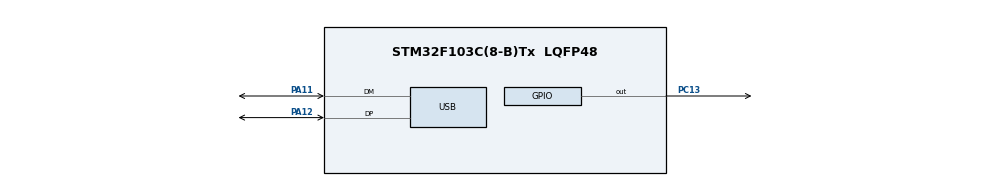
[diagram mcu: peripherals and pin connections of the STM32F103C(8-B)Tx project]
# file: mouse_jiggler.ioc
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Mcu.Family=STM32F1
Mcu.Name=STM32F103C(8-B)Tx
Mcu.Package=LQFP48
NVIC.PriorityGroup=NVIC_PRIORITYGROUP_4
NVIC.USB_LP_CAN1_RX0_IRQn=true\:0\:0\:false\:false\:true\:false\:true\:true
PA11.Mode=Device
PA11.Signal=USB_DM
PA12.Mode=Device
PA12.Signal=USB_DP
PA13.Mode=Serial_Wire
PA13.Signal=SYS_JTMS-SWDIO
PA14.Mode=Serial_Wire
PA14.Signal=SYS_JTCK-SWCLK
PC13-TAMPER-RTC.Signal=GPIO_Output
PD0-OSC_IN.Mode=HSE-External-Oscillator
PD0-OSC_IN.Signal=RCC_OSC_IN
PD1-OSC_OUT.Mode=HSE-External-Oscillator
PD1-OSC_OUT.Signal=RCC_OSC_OUT
ProjectManager.HeapSize=0x1000
ProjectManager.StackSize=0x1000
ProjectManager.TargetToolchain=STM32CubeIDE
RCC.AHBFreq_Value=72000000
RCC.APB1CLKDivider=RCC_HCLK_DIV2
RCC.APB1Freq_Value=36000000
RCC.APB1TimFreq_Value=72000000
RCC.APB2Freq_Value=72000000
RCC.APB2TimFreq_Value=72000000
RCC.HCLKFreq_Value=72000000
RCC.PLLMUL=RCC_PLL_MUL9
RCC.SYSCLKFreq_VALUE=72000000
RCC.SYSCLKSource=RCC_SYSCLKSOURCE_PLLCLK
RCC.USBFreq_Value=48000000
RCC.USBPrescaler=RCC_USBCLKSOURCE_PLL_DIV1_5
USB_DEVICE.CLASS_NAME_FS=HID
USB_DEVICE.VirtualMode=Hid
USB_DEVICE.VirtualModeFS=Hid_FS
VP_USB_DEVICE_VS_USB_DEVICE_HID_FS.Mode=HID_FS
board=custom

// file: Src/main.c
/* USER CODE BEGIN Header */
/**
  ******************************************************************************
  * @file           : main.c
  * @brief          : Main program body
  ******************************************************************************
  * @attention
  *
  * Copyright (c) 2026 STMicroelectronics.
  * All rights reserved.
  *
  * This software is licensed under terms that can be found in the LICENSE file
  * in the root directory of this software component.
  * If no LICENSE file comes with this software, it is provided AS-IS.
  *
  ******************************************************************************
  */
/* USER CODE END Header */
#include "main.h"
#include "usb_device.h"

/* USER CODE BEGIN Includes */
#include <stdlib.h>
#include <math.h>
#include "usbd_def.h"
#include "usbd_hid.h"
/* USER CODE END Includes */

/* USER CODE BEGIN PD */

#ifndef M_PI
#define M_PI 3.14159265358979323846
#endif

#define STARTUP_DELAY_MS   3000
#define LED_BLINK_WAIT_MS  1000   // full period while waiting (USB OK)
#define LED_BLINK_WORK_MS  500    // full period while moving
#define LED_BLINK_NO_HOST_MS 150  // continuous fast blink: no host setup packets
#define LED_DBG_CYCLE_MS     2500 // pause between burst groups
#define LED_DBG_SLOT_MS      400  // one blink slot within a burst
#define LED_DBG_ON_MS        200  // on-time within each slot

/* Jiggler movement tuning */
#define JIGGLE_WAIT_MIN_MS      3000
#define JIGGLE_WAIT_RANGE_MS    5000   // 3-8 s between moves
#define JIGGLE_STEP_MIN_MS      16
#define JIGGLE_STEP_RANGE_MS      8    // 16-24 ms between HID updates
#define JIGGLE_MOVE_MIN_MS       900
#define JIGGLE_MOVE_RANGE_MS     600   // each move lasts 0.9-1.5 s
#define JIGGLE_MAX_DELTA           2   // pixels per report

/*
 * USB on STM32F103 needs 72 MHz PLL -> 48 MHz USB clock.
 *   USE_HSI_CLOCK 0  - HSE crystal (recommended; use BOARD_HSE_MHZ)
 *   USE_HSI_CLOCK 1  - HSI only (64 MHz max; USB clock out of spec, test only)
 *   BOARD_HSE_MHZ  8  - crystal marked 8.000 (PLL x9)
 *   BOARD_HSE_MHZ 12  - crystal marked 12.000 (PLL x6)
 */
#ifndef USE_HSI_CLOCK
#define USE_HSI_CLOCK 0
#endif
#ifndef BOARD_HSE_MHZ
#define BOARD_HSE_MHZ 8
#endif

/* USER CODE END PD */

/* USER CODE BEGIN PV */
/* ---- App state machine ---- */
typedef enum { APP_STARTUP, APP_WAITING, APP_MOVING } AppState;
static AppState app_state = APP_STARTUP;

static uint32_t startup_tick = 0;
static uint32_t led_last_toggle = 0;
static uint8_t  led_state = 0;
static uint8_t  startup_started = 0;

/* ---- Jiggler state ---- */
typedef enum { JIGGLE_WAITING, JIGGLE_MOVING } JiggleState;
static JiggleState jiggle_state = JIGGLE_WAITING;

static uint32_t next_action_tick = 0;
static uint32_t last_step_tick = 0;

static float ellipse_a;
static float ellipse_b;
static float rotation;
static float start_angle;
static float sweep_angle;
static float sent_x, sent_y;
static uint32_t step_interval_ms;
static uint32_t move_start_tick;
static uint32_t move_duration_ms;

static uint8_t hid_report[4] = {0};
extern USBD_HandleTypeDef hUsbDeviceFS;

/* USER CODE END PV */

void SystemClock_Config(void);
static void MX_GPIO_Init(void);

/* USER CODE BEGIN 0 */

/* ---------- LED helpers ---------- */
/* Blue Pill onboard LED is active-LOW: pin LOW = LED on.
   If your clone is inverted, swap SET/RESET in both functions below. */
static void led_toggle(void)
{
    led_state = !led_state;
    HAL_GPIO_WritePin(GPIOC, GPIO_PIN_13, led_state ? GPIO_PIN_RESET : GPIO_PIN_SET);
}

static void led_off(void)
{
    HAL_GPIO_WritePin(GPIOC, GPIO_PIN_13, GPIO_PIN_SET);
    led_state = 0;
}

/* Not configured: fast blink = no setup packets; N blinks/cycle = dev_state (1 or 2). */
static void led_usb_not_configured(uint32_t now)
{
    static uint32_t cycle_start = 0U;
    static uint8_t cycle_started = 0U;

    if (USB_GetSetupCount() == 0U)
    {
        cycle_started = 0U;
        if (now - led_last_toggle >= LED_BLINK_NO_HOST_MS / 2U)
        {
            led_toggle();
            led_last_toggle = now;
        }
        return;
    }

    if (!cycle_started)
    {
        cycle_start = now;
        cycle_started = 1U;
        led_off();
    }

    uint8_t blinks = USB_GetDevState();
    if (blinks < 1U)
    {
        blinks = 1U;
    }
    if (blinks > 4U)
    {
        blinks = 4U;
    }

    uint32_t elapsed = now - cycle_start;
    if (elapsed >= LED_DBG_CYCLE_MS)
    {
        cycle_start = now;
        elapsed = 0U;
        led_off();
    }

    uint32_t slot = elapsed / LED_DBG_SLOT_MS;
    uint32_t in_slot = elapsed % LED_DBG_SLOT_MS;

    if (slot < blinks)
    {
        uint8_t on = (in_slot < LED_DBG_ON_MS) ? 1U : 0U;
        if (on != led_state)
        {
            if (on)
            {
                HAL_GPIO_WritePin(GPIOC, GPIO_PIN_13, GPIO_PIN_RESET);
            }
            else
            {
                HAL_GPIO_WritePin(GPIOC, GPIO_PIN_13, GPIO_PIN_SET);
            }
            led_state = on;
        }
    }
    else
    {
        led_off();
    }
}

/* ---------- HID send ---------- */
static uint8_t hid_endpoint_ready(void)
{
    uint8_t state = hUsbDeviceFS.dev_state;

    if (state != USBD_STATE_CONFIGURED && state != USBD_STATE_SUSPENDED)
        return 0;
    if (hUsbDeviceFS.pClassData == NULL)
        return 0;

    USBD_HID_HandleTypeDef *hhid = (USBD_HID_HandleTypeDef *)hUsbDeviceFS.pClassData;
    return (hhid->state == HID_IDLE);
}

/* Returns 1 if the report was accepted by the USB stack. */
static uint8_t send_hid_move(int8_t dx, int8_t dy)
{
    USBD_HID_HandleTypeDef *hhid;

    if (!hid_endpoint_ready())
        return 0;

    hid_report[0] = 0;
    hid_report[1] = (uint8_t)dx;
    hid_report[2] = (uint8_t)dy;
    hid_report[3] = 0;
    USBD_HID_SendReport(&hUsbDeviceFS, hid_report, 4);

    hhid = (USBD_HID_HandleTypeDef *)hUsbDeviceFS.pClassData;
    return (hhid != NULL && hhid->state == HID_BUSY);
}

/* ---------- random helper ---------- */
static float randf(float min, float max)
{
    return min + ((float)rand() / (float)RAND_MAX) * (max - min);
}

static int8_t clamp_delta(int v)
{
    if (v > JIGGLE_MAX_DELTA)
        return (int8_t)JIGGLE_MAX_DELTA;
    if (v < -JIGGLE_MAX_DELTA)
        return (int8_t)(-JIGGLE_MAX_DELTA);
    return (int8_t)v;
}

/* ---------- ellipse math ---------- */
static void ellipse_point(float t, float *x, float *y)
{
    float ex = ellipse_a * cosf(t);
    float ey = ellipse_b * sinf(t);
    *x = ex * cosf(rotation) - ey * sinf(rotation);
    *y = ex * sinf(rotation) + ey * cosf(rotation);
}

/* ---------- start a new curved move ---------- */
static void start_new_move(void)
{
    uint32_t now = HAL_GetTick();

    ellipse_a   = randf(12.0f, 28.0f);
    ellipse_b   = randf(8.0f, 20.0f);
    rotation    = randf(0.0f, 2.0f * M_PI);
    start_angle = randf(0.0f, 2.0f * M_PI);
    sweep_angle = randf(M_PI * 0.6f, M_PI * 1.6f);
    if (rand() % 2) sweep_angle = -sweep_angle;

    sent_x = 0.0f;
    sent_y = 0.0f;
    move_start_tick = now;
    move_duration_ms = JIGGLE_MOVE_MIN_MS + (rand() % (JIGGLE_MOVE_RANGE_MS + 1));
    step_interval_ms = JIGGLE_STEP_MIN_MS + (rand() % (JIGGLE_STEP_RANGE_MS + 1));

    jiggle_state = JIGGLE_MOVING;
    last_step_tick = now;
}

/* ---------- advance one step of the current move ---------- */
static void jiggler_step(void)
{
    uint32_t now = HAL_GetTick();
    float move_t, eased, angle, x, y, dx, dy;
    int8_t idx, idy;
    uint32_t elapsed;

    if (now - last_step_tick < step_interval_ms)
        return;

    elapsed = now - move_start_tick;
    move_t = (float)elapsed / (float)move_duration_ms;
    if (move_t > 1.0f)
        move_t = 1.0f;

    eased = 0.5f - 0.5f * cosf(move_t * (float)M_PI);
    angle = start_angle + sweep_angle * eased;
    ellipse_point(angle, &x, &y);

    dx = x - sent_x;
    dy = y - sent_y;

    /* Move complete: duration elapsed and cursor caught up to the path. */
    if (move_t >= 1.0f && (dx * dx + dy * dy) < 4.0f)
    {
        jiggle_state = JIGGLE_WAITING;
        next_action_tick = now + (JIGGLE_WAIT_MIN_MS + (rand() % (JIGGLE_WAIT_RANGE_MS + 1)));
        last_step_tick = now;
        return;
    }

    if (fabsf(dx) < 0.01f && fabsf(dy) < 0.01f)
    {
        last_step_tick = now;
        return;
    }

    idx = clamp_delta((int)roundf(dx));
    idy = clamp_delta((int)roundf(dy));

    if (idx == 0 && idy == 0)
    {
        if (fabsf(dx) >= fabsf(dy))
            idx = (dx > 0.0f) ? 1 : -1;
        else
            idy = (dy > 0.0f) ? 1 : -1;
    }

    if (!send_hid_move(idx, idy))
        return;

    sent_x += (float)idx;
    sent_y += (float)idy;
    last_step_tick = now;
}

/* ---------- top-level poll, call every loop iteration ---------- */
static void app_poll(void)
{
    uint32_t now = HAL_GetTick();

    if (!USB_IsConfigured())
    {
        led_usb_not_configured(now);
        return;
    }

    switch (app_state)
    {
        case APP_STARTUP:
            if (!startup_started)
            {
                startup_tick = now;
                led_last_toggle = now;
                startup_started = 1;
            }

            if (now - led_last_toggle >= LED_BLINK_WAIT_MS / 2)
            {
                led_toggle();
                led_last_toggle = now;
            }

            if (now - startup_tick >= STARTUP_DELAY_MS)
            {
                app_state = APP_WAITING;
                next_action_tick = now + (JIGGLE_WAIT_MIN_MS + (rand() % (JIGGLE_WAIT_RANGE_MS + 1)));
                led_last_toggle = now;
            }
            break;

        case APP_WAITING:
            if (now - led_last_toggle >= LED_BLINK_WAIT_MS / 2)
            {
                led_toggle();
                led_last_toggle = now;
            }

            if (now >= next_action_tick)
            {
                start_new_move();
                app_state = APP_MOVING;
                led_last_toggle = now;
            }
            break;

        case APP_MOVING:
            if (now - led_last_toggle >= LED_BLINK_WORK_MS / 2)
            {
                led_toggle();
                led_last_toggle = now;
            }

            jiggler_step();

            if (jiggle_state == JIGGLE_WAITING)
            {
                app_state = APP_WAITING;
                led_last_toggle = now;
            }
            break;
    }
}

/* USER CODE END 0 */

int main(void)
{

  /* MCU Configuration--------------------------------------------------------*/

  /* Reset of all peripherals, Initializes the Flash interface and the Systick. */
  HAL_Init();

  /* Configure the system clock */
  SystemClock_Config();

  /* Initialize all configured peripherals */
  MX_GPIO_Init();
  MX_USB_DEVICE_Init();
  /* USER CODE BEGIN 2 */
  srand(HAL_GetTick() ^ (uint32_t)&hid_report);
  led_off();
  /* USER CODE END 2 */

  /* Infinite loop */
  /* USER CODE BEGIN WHILE */
  while (1)
  {
	  app_poll();

    /* USER CODE END WHILE */

  }
}

void SystemClock_Config(void)
{
  RCC_OscInitTypeDef RCC_OscInitStruct = {0};
  RCC_ClkInitTypeDef RCC_ClkInitStruct = {0};
  RCC_PeriphCLKInitTypeDef PeriphClkInit = {0};

#if USE_HSI_CLOCK
  /* HSI/2 x16 = 64 MHz (F103 PLL max). USB = 42.7 MHz, not spec-compliant. */
  RCC_OscInitStruct.OscillatorType = RCC_OSCILLATORTYPE_HSI;
  RCC_OscInitStruct.HSIState = RCC_HSI_ON;
  RCC_OscInitStruct.PLL.PLLState = RCC_PLL_ON;
  RCC_OscInitStruct.PLL.PLLSource = RCC_PLLSOURCE_HSI_DIV2;
  RCC_OscInitStruct.PLL.PLLMUL = RCC_PLL_MUL16;
  if (HAL_RCC_OscConfig(&RCC_OscInitStruct) != HAL_OK)
  {
    Error_Handler();
  }
#else
  /** HSE -> PLL = 72 MHz SYSCLK, USB = 48 MHz; fall back to HSI if HSE fails */
  RCC_OscInitStruct.OscillatorType = RCC_OSCILLATORTYPE_HSE;
  RCC_OscInitStruct.HSEState = RCC_HSE_ON;
  RCC_OscInitStruct.HSEPredivValue = RCC_HSE_PREDIV_DIV1;
  RCC_OscInitStruct.HSIState = RCC_HSI_ON;
  RCC_OscInitStruct.PLL.PLLState = RCC_PLL_ON;
  RCC_OscInitStruct.PLL.PLLSource = RCC_PLLSOURCE_HSE;
#if BOARD_HSE_MHZ == 12
  RCC_OscInitStruct.PLL.PLLMUL = RCC_PLL_MUL6;
#elif BOARD_HSE_MHZ == 8
  RCC_OscInitStruct.PLL.PLLMUL = RCC_PLL_MUL9;
#else
#error "BOARD_HSE_MHZ must be 8 or 12"
#endif
  if (HAL_RCC_OscConfig(&RCC_OscInitStruct) != HAL_OK)
  {
    Error_Handler();
  }
  if (__HAL_RCC_GET_FLAG(RCC_FLAG_HSERDY) == RESET)
  {
    Error_Handler();
  }
#endif

  RCC_ClkInitStruct.ClockType = RCC_CLOCKTYPE_HCLK|RCC_CLOCKTYPE_SYSCLK
                              |RCC_CLOCKTYPE_PCLK1|RCC_CLOCKTYPE_PCLK2;
  RCC_ClkInitStruct.SYSCLKSource = RCC_SYSCLKSOURCE_PLLCLK;
  RCC_ClkInitStruct.AHBCLKDivider = RCC_SYSCLK_DIV1;
  RCC_ClkInitStruct.APB1CLKDivider = RCC_HCLK_DIV2;
  RCC_ClkInitStruct.APB2CLKDivider = RCC_HCLK_DIV1;

  if (HAL_RCC_ClockConfig(&RCC_ClkInitStruct, FLASH_LATENCY_2) != HAL_OK)
  {
    Error_Handler();
  }

  PeriphClkInit.PeriphClockSelection = RCC_PERIPHCLK_USB;
  PeriphClkInit.UsbClockSelection = RCC_USBCLKSOURCE_PLL_DIV1_5;
  if (HAL_RCCEx_PeriphCLKConfig(&PeriphClkInit) != HAL_OK)
  {
    Error_Handler();
  }
}

static void MX_GPIO_Init(void)
{
  GPIO_InitTypeDef GPIO_InitStruct = {0};

  /* GPIO Ports Clock Enable */
  __HAL_RCC_GPIOC_CLK_ENABLE();
  __HAL_RCC_GPIOD_CLK_ENABLE();
  __HAL_RCC_GPIOA_CLK_ENABLE();

  /*Configure GPIO pin Output Level */
  HAL_GPIO_WritePin(GPIOC, GPIO_PIN_13, GPIO_PIN_RESET);

  /*Configure GPIO pin : PC13 */
  GPIO_InitStruct.Pin = GPIO_PIN_13;
  GPIO_InitStruct.Mode = GPIO_MODE_OUTPUT_PP;
  GPIO_InitStruct.Pull = GPIO_NOPULL;
  GPIO_InitStruct.Speed = GPIO_SPEED_FREQ_LOW;
  HAL_GPIO_Init(GPIOC, &GPIO_InitStruct);

}

void Error_Handler(void)
{
  /* USER CODE BEGIN Error_Handler_Debug */
  while (1)
  {
    HAL_GPIO_TogglePin(GPIOC, GPIO_PIN_13);
    HAL_Delay(50);
  }
  /* USER CODE END Error_Handler_Debug */
}
